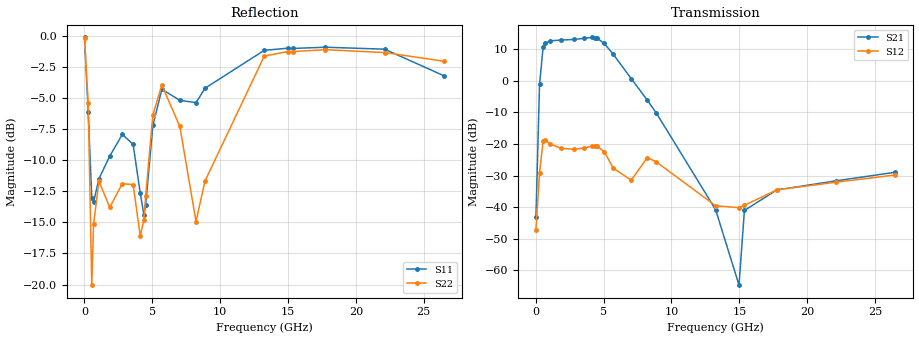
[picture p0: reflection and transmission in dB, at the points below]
!Agilent Technologies,N5242A,MY52422126,A.09.90.01
!Agilent N5242A: A.09.90.01
!Date: Wednesday, November 18, 2015 20:41:38
!Correction: S11(Full 2 Port(1,2))
!S21(Full 2 Port(1,2))
!S12(Full 2 Port(1,2))
!S22(Full 2 Port(1,2))
!S2P File: Measurements: S11, S21, S12, S22:
# Hz S  dB  R 50
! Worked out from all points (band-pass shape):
!   201 points, 10 MHz to 26.5 GHz, reference 50 ohm
!   highest |S21| = 13.80 dB at 4.116 GHz (marker M1); lowest = -64.7 dB at 14.98 GHz (marker M2)
!   |S21| within 3 dB of the highest: 547.8 MHz to 5.264 GHz (4.717 GHz wide, 162 % of centre)
!   lowest |S11| = -14.4 dB at 4.381 GHz (marker M3), VSWR 1.47, Z = 34.1 + j0.448 ohm
!   |S11| at or under -10 dB: 426.8 MHz to 1.734 GHz (1.307 GHz wide, 121 % of centre); 3.815 GHz to 4.779 GHz (964.2 MHz wide, 22.4 % of centre)
!   |S22| runs from -20.1 to -0.2 dB; largest |S21 - S12| = 4.9
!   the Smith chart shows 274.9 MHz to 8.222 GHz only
!   S11 on the Smith chart (normalised r, x): 274.9 MHz: 0.34, +0.12; 672.2 MHz: 1.32, -0.39; 3.586 GHz: 0.47, +0.10; 5.705 GHz: 0.26, +0.23; 7.03 GHz: 0.97, +1.30; 8.222 GHz: 1.69, -1.51
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1e7  -0.13 -11.4  -43.17 81.9  -47.11 54.5  -0.19 -9.4
2.749e8  -6.13 165.0  -1.08 -39.2  -29.11 138.6  -5.38 -173.2
5.398e8  -13.01 21.4  10.73 -118.0  -19.05 47.5  -20.05 3.1
6.7225e8  -13.39 -41.3  11.98 -147.6  -18.73 17.9  -15.14 -83.7
1.0696e9  -11.49 -111.4  12.71 157.0  -19.95 -30.1  -11.69 -147.0
1.8643e9  -9.68 -143.1  12.95 86.5  -21.38 -79.3  -13.80 -169.0
2.79145e9  -7.93 -167.8  13.14 17.5  -21.65 -126.2  -11.89 -174.2
3.58615e9  -8.73 164.9  13.51 -42.7  -21.26 -167.4  -11.97 142.0
4.11595e9  -12.67 157.9  13.80 -87.4  -20.70 159.4  -16.12 67.9
4.38085e9  -14.43 178.1  13.73 -112.4  -20.62 139.8  -14.78 0.4
4.5133e9  -13.57 -169.0  13.58 -125.4  -20.74 129.2  -12.88 -27.7
5.0431e9  -7.21 -170.1  11.88 -177.1  -22.40 85.8  -6.36 -96.6
5.70535e9  -4.30 152.7  8.46 126.3  -27.61 35.4  -3.96 -149.1
7.02985e9  -5.19 57.9  0.76 29.1  -31.49 77.6  -7.29 137.0
8.2219e9  -5.38 -36.1  -6.12 -44.8  -24.29 2.3  -14.94 40.9
8.88415e9  -4.22 -73.3  -10.18 -85.4  -25.66 -53.0  -11.68 -44.7
1.3255e10  -1.17 -179.2  -40.82 149.3  -39.57 -123.9  -1.63 -174.1
1.497685e10  -1.00 160.6  -64.71 -17.1  -40.16 -142.1  -1.27 164.1
1.53742e10  -1.02 156.7  -41.05 -86.0  -39.42 -140.2  -1.27 159.7
1.77583e10  -0.92 134.0  -34.55 -176.8  -34.53 -176.7  -1.12 136.1
2.212915e10  -1.08 97.1  -31.66 52.2  -32.10 52.3  -1.35 99.4
2.65e10  -3.22 74.6  -28.94 -109.6  -29.80 -103.0  -2.05 73.3
